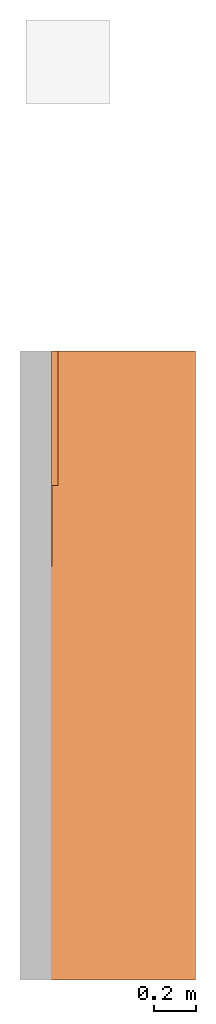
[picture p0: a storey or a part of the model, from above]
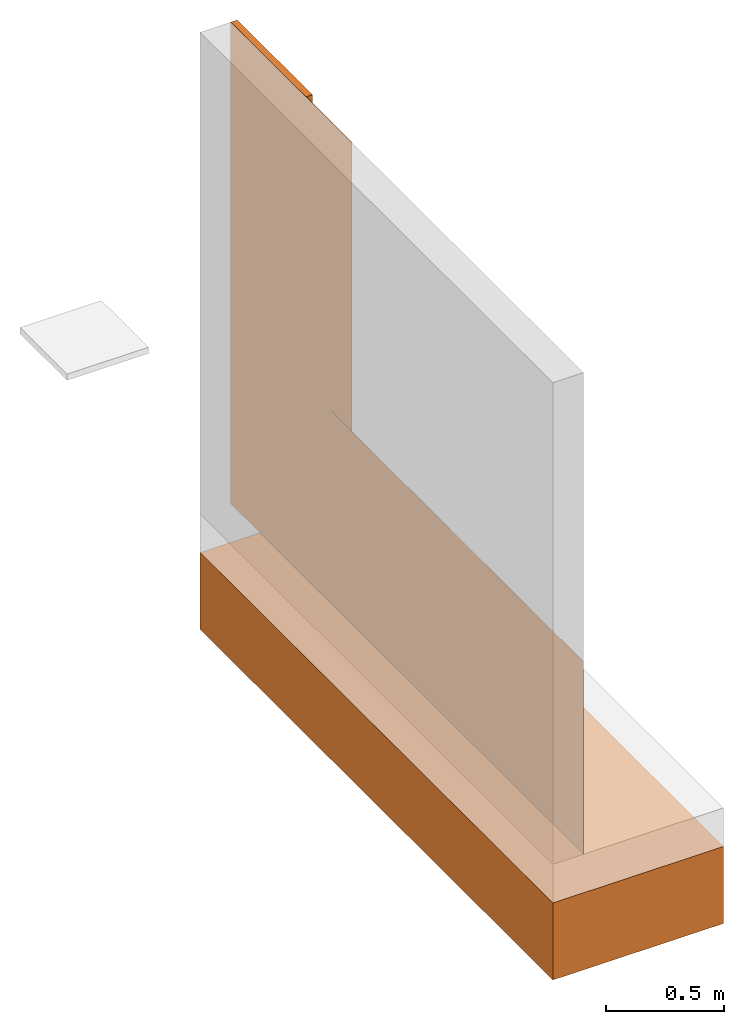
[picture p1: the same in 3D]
Properties of the parts of a building model (IFC2X3)

# File
Description: ViewDefinition [CoordinationView_V2.0], RevitIdentifiers [VersionGUID: 7b8637ec-bbda-45e2-8097-0668c041d873, NumberOfSaves: 19], CoordinateReference [CoordinateBase: Coordenadas compartilhadas]
File name: 0001
Time: 2026-02-06T09:33:47
Written by: ODA IFC SDK 22.8
Made in: 22.1.50.17 - Exporter 22.6.2.0 - IU alternativa 22.6.2.0

# IfcProject, 0001
LongName: Circulação de Pedestres em contato com o solo - VIAPLUS 2000 Fibras; Phase: Status do projeto

# IfcSite, Default
RefLatitude: 42, 21, 31, 181944; RefLongitude: -71, -3, -24, -263304; RefElevation: 0 m

# IfcBuilding
Pset_BuildingCommon - NumberOfStoreys: 1; IsLandmarked: no

# IfcBuildingStorey: Nível:Cabeça de 8 mm, ARQ Térreo
LongName: ARQ Térreo; Elevation: -0.0025238 m

# IfcBuildingElementProxy: IMPER:IMPER:433934, IMPER:IMPER:433934:IMPER:433934 : IMPER:IMPER:433934:299675
In: ARQ Térreo
Type - Material: #Viaplus 2000, #reboco, #chapisco, #solo
Type - Pset_BuildingElementProxyCommon - Reference: IMPER
Type - Pset_QuantityTakeOff - Reference: IMPER
Type - Pset_ProvisionForVoid - Width: 0.952886 m; Height: 0.00103887 m; Depth: 2.6 m
Pset_BuildingElementProxyCommon - sets with these values: 2

# IfcSlab: Piso:IMPH_VP1000, Piso:IMPH_VP1000:293954
In: ARQ Térreo
Type - PredefinedType: FLOOR; Material: #reboco 0.03 m, #chapisco 0.001 m, #Viaplus 2000 0.001 m
Type - Pset_SlabCommon - IsExternal: no
Pset_QuantityTakeOff - Reference: IMPH_VP1000; sets with these values: 2
Pset_SlabCommon - Reference: IMPH_VP1000; LoadBearing: no; PitchAngle: 0 deg

# IfcSlab: Piso:Piso:LAJE CONCRETO, Piso:Piso:LAJE CONCRETO:299703
In: ARQ Térreo
Type - PredefinedType: FLOOR; Material: #concreto 0.2 m
Type - Pset_SlabCommon - IsExternal: no
Pset_QuantityTakeOff - Reference: Piso:LAJE CONCRETO; sets with these values: 2
Pset_SlabCommon - LoadBearing: no; PitchAngle: 0 deg; Reference: Piso:LAJE CONCRETO

# IfcWallStandardCase: Parede básica:Parede de Alvenaria 2, Parede básica:Parede Concreto:395312
In: ARQ Térreo
Type - PredefinedType: STANDARD; Material: Alvanearia 0.15 m
Type - Pset_WallCommon - IsExternal: yes; ThermalTransmittance: 6.97333 kg/K/s3
Pset_QuantityTakeOff - Reference: Parede Concreto; sets with these values: 2
Pset_WallCommon - LoadBearing: no; Reference: Parede Concreto; ExtendToStructure: no
